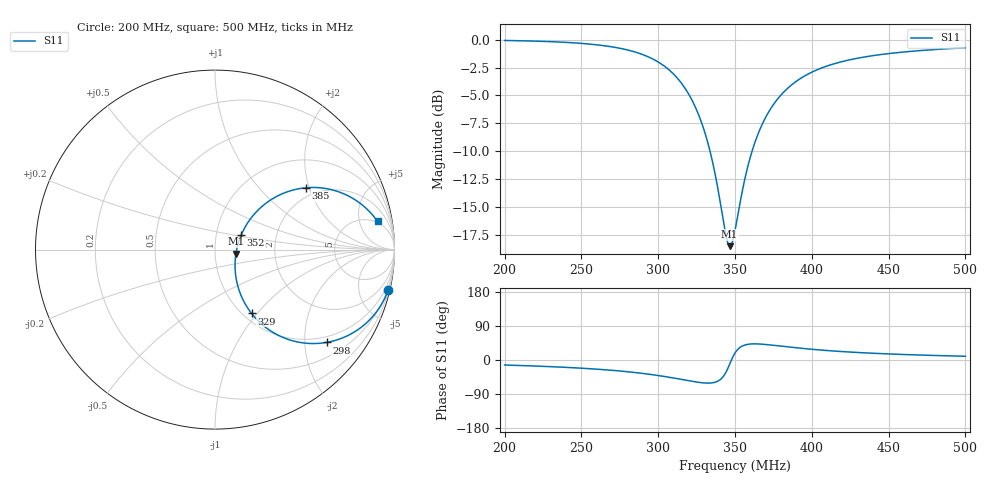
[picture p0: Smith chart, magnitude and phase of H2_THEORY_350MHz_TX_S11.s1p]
! THEORETICAL_SURROGATE_ONLY - NOT VNA MEASUREMENT
! 350 MHz-centered 0.48-lambda center-fed dipole theory surrogate
! total length=0.411143942 m; each arm=0.205571971 m; assumed wire radius=0.001000 m
! 601 points, 200-500 MHz, 50-ohm reference
# Hz S RI R 50
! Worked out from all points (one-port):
!   601 points, 200 MHz to 500 MHz, reference 50 ohm
!   lowest |S11| = -18.5 dB at 346.5 MHz (marker M1), VSWR 1.27, Z = 63.1 - j2.94 ohm
!   |S11| at or under -10 dB: 333.7 MHz to 361.1 MHz (27.35 MHz wide, 7.87 % of centre)
!   S11 on the Smith chart (normalised r, x): 200 MHz: 0.33, -8.62; 298 MHz: 0.84, -2.52; 329 MHz: 1.09, -0.94; 352 MHz: 1.32, +0.22; 385 MHz: 1.72, +1.90; 500 MHz: 5, +9
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2e8  0.965 -0.2266
2.375e8  0.9212 -0.3159
2.58e8  0.8714 -0.381
2.75e8  0.8001 -0.4435
2.87e8  0.7221 -0.4872
2.98e8  0.6213 -0.5172
3.06e8  0.5268 -0.523
3.125e8  0.4377 -0.5094
3.215e8  0.3052 -0.45
3.29e8  0.2038 -0.3558
3.335e8  0.1565 -0.2804
3.38e8  0.1249 -0.1946
3.44e8  0.1119 -0.0731
3.465e8  0.1165 -0.023
3.48e8  0.122 0.00627
3.5e8  0.1322 0.044
3.52e8  0.1454 0.0798
3.555e8  0.1747 0.1374
3.585e8  0.2047 0.1807
3.655e8  0.2851 0.2593
3.74e8  0.387 0.3162
3.85e8  0.5054 0.3444
3.875e8  0.5292 0.346
4.05e8  0.6622 0.3304
4.25e8  0.7593 0.2902
4.42e8  0.8129 0.2545
4.625e8  0.8568 0.2156
5e8  0.9055 0.1576
